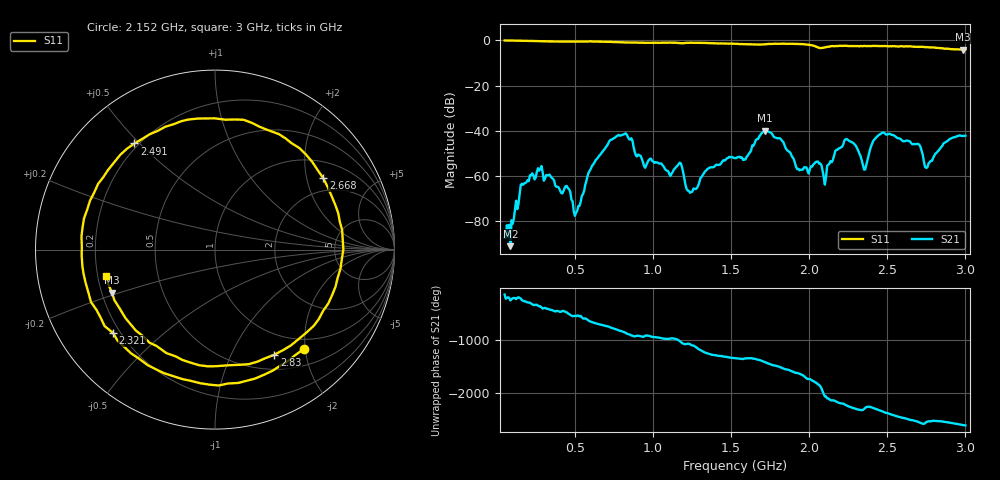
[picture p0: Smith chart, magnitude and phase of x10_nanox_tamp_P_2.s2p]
! nanovna_capture.py 2026-10-18T20:59:28+0900
! NanoVNA-F_V2 fw 0.6.0 SN 4A3639384505514B
! cal: load open short thru cal'ed  over 50000000-3000000000 Hz, 201 points
! points 401, avg 4
! S21: port1 = green ~10 mm H loop (flat, tape), port2 = GSM antenna; modified (implanted) Nano X at position P (P = user-found best placement), placement 2
# HZ S RI R 50
! S12 and S22 are not measured (written as 0)
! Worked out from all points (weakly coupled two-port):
!   401 points, 50 MHz to 3 GHz, reference 50 ohm
!   highest |S21| = -39.98 dB at 1.717 GHz (marker M1); lowest = -90.9 dB at 86.88 MHz (marker M2)
!   lowest |S11| = -4.1 dB at 2.985 GHz (marker M3), VSWR 4.29, Z = 12.1 - j9.48 ohm
!   |S11| at or under -10 dB: nowhere
!   S12 and S22 are empty: the file has one direction only
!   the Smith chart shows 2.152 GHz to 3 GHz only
!   S11 on the Smith chart (normalised r, x): 2.152 GHz: 0.79, -1.97; 2.321 GHz: 0.17, -0.35; 2.491 GHz: 0.18, +0.48; 2.668 GHz: 1.52, +2.52; 2.83 GHz: 0.69, -1.48; 3 GHz: 0.24, -0.11
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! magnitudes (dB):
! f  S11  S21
! 50 MHz  -0.1  -87.2
! 86.88 MHz  -0.1  -90.9
! 271.2 MHz  -0.4  -57.6
! 507.2 MHz  -0.6  -76.2
! 544.1 MHz  -0.6  -68.8
! 765.4 MHz  -0.8  -42.4
! 1.038 GHz  -1.1  -54.4
! 1.171 GHz  -1.3  -54.1
! 1.237 GHz  -1.1  -67.4
! 1.525 GHz  -1.6  -52.0
! 1.717 GHz  -1.8  -40.0
! 2.019 GHz  -2.2  -55.7
! 2.152 GHz  -2.6  -52.9
! 2.321 GHz  -2.7  -50.1
! 2.358 GHz  -2.6  -57.1
! 2.491 GHz  -2.6  -41.6
! 2.513 GHz  -2.7  -41.3
! 2.668 GHz  -2.8  -45.8
! 2.749 GHz  -3.1  -56.4
! 2.83 GHz  -3.4  -48.6
! 2.985 GHz  -4.1  -42.2
! 3 GHz  -4.1  -42.1
